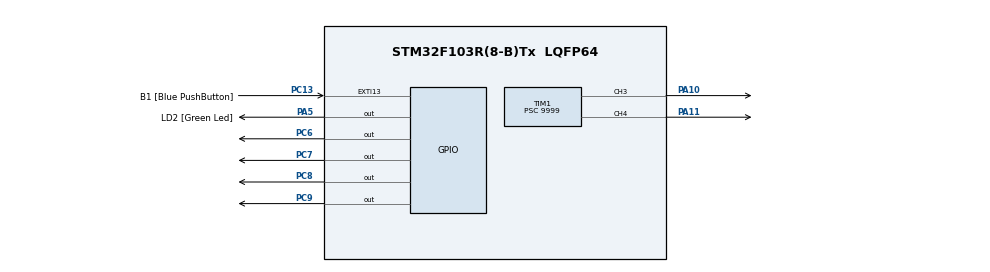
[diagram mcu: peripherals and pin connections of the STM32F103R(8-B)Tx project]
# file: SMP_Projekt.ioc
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Mcu.Family=STM32F1
Mcu.Name=STM32F103R(8-B)Tx
Mcu.Package=LQFP64
NVIC.EXTI15_10_IRQn=true\:0\:0\:false\:false\:true\:true\:true
NVIC.PriorityGroup=NVIC_PRIORITYGROUP_4
PA10.Signal=S_TIM1_CH3
PA11.Signal=S_TIM1_CH4
PA13.GPIO_Label=TMS
PA13.Mode=Serial_Wire
PA13.Signal=SYS_JTMS-SWDIO
PA14.GPIO_Label=TCK
PA14.Mode=Serial_Wire
PA14.Signal=SYS_JTCK-SWCLK
PA2.GPIO_Label=USART_TX
PA2.GPIO_Mode=GPIO_MODE_AF_PP
PA2.GPIO_PuPd=GPIO_NOPULL
PA2.GPIO_Speed=GPIO_SPEED_FREQ_LOW
PA2.Signal=USART2_TX
PA3.GPIO_Label=USART_RX
PA3.GPIO_Mode=GPIO_MODE_AF_PP
PA3.GPIO_PuPd=GPIO_NOPULL
PA3.GPIO_Speed=GPIO_SPEED_FREQ_LOW
PA3.Signal=USART2_RX
PA5.GPIO_Label=LD2 [Green Led]
PA5.GPIO_ModeDefaultOutputPP=GPIO_MODE_OUTPUT_PP
PA5.GPIO_PuPd=GPIO_NOPULL
PA5.GPIO_Speed=GPIO_SPEED_FREQ_LOW
PA5.Signal=GPIO_Output
PB3.GPIO_Label=SWO
PB3.Signal=SYS_JTDO-TRACESWO
PC13-TAMPER-RTC.GPIO_Label=B1 [Blue PushButton]
PC13-TAMPER-RTC.GPIO_ModeDefaultEXTI=GPIO_MODE_IT_FALLING
PC13-TAMPER-RTC.GPIO_PuPd=GPIO_NOPULL
PC13-TAMPER-RTC.Signal=GPXTI13
PC14-OSC32_IN.Signal=RCC_OSC32_IN
PC15-OSC32_OUT.Signal=RCC_OSC32_OUT
PC6.Signal=GPIO_Output
PC7.Signal=GPIO_Output
PC8.Signal=GPIO_Output
PC9.Signal=GPIO_Output
PD0-OSC_IN.Signal=RCC_OSC_IN
PD1-OSC_OUT.Signal=RCC_OSC_OUT
ProjectManager.HeapSize=0x200
ProjectManager.StackSize=0x400
ProjectManager.TargetToolchain=STM32CubeIDE
RCC.AHBFreq_Value=64000000
RCC.APB1CLKDivider=RCC_HCLK_DIV2
RCC.APB1Freq_Value=32000000
RCC.APB1TimFreq_Value=64000000
RCC.APB2CLKDivider=RCC_HCLK_DIV16
RCC.APB2Freq_Value=4000000
RCC.APB2TimCLKDivider=2
RCC.APB2TimFreq_Value=8000000
RCC.HCLKFreq_Value=64000000
RCC.SYSCLKFreq_VALUE=64000000
RCC.SYSCLKSource=RCC_SYSCLKSOURCE_PLLCLK
RCC.USBFreq_Value=64000000
SH.S_TIM1_CH3.0=TIM1_CH3,PWM Generation3 CH3
SH.S_TIM1_CH4.0=TIM1_CH4,PWM Generation4 CH4
TIM1.Channel-PWM\ Generation3\ CH3=TIM_CHANNEL_3
TIM1.Channel-PWM\ Generation4\ CH4=TIM_CHANNEL_4
TIM1.Period=7
TIM1.Prescaler=9999
VP_TIM1_VS_ClockSourceINT.Mode=Internal
board=NUCLEO-F103RB

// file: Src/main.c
/* USER CODE BEGIN Header */
/**
  ******************************************************************************
  * @file           : main.c
  * @brief          : Main program body
  ******************************************************************************
  * @attention
  *
  * <h2><center>&copy; Copyright (c) 2020 STMicroelectronics.
  * All rights reserved.</center></h2>
  *
  * This software component is licensed by ST under BSD 3-Clause license,
  * the "License"; You may not use this file except in compliance with the
  * License. You may obtain a copy of the License at:
  *                        opensource.org/licenses/BSD-3-Clause
  *
  ******************************************************************************
  */
/* USER CODE END Header */

#include "main.h"
#include "tim.h"
#include "gpio.h"

void SystemClock_Config(void);

int main(void)
{

  /* MCU Configuration--------------------------------------------------------*/

  /* Reset of all peripherals, Initializes the Flash interface and the Systick. */
  HAL_Init();

  /* Configure the system clock */
  SystemClock_Config();

  /* Initialize all configured peripherals */
  MX_GPIO_Init();
  MX_TIM1_Init();
  /* USER CODE BEGIN 2 */

  HAL_TIM_PWM_Start(&htim1, TIM_CHANNEL_3);
  HAL_TIM_PWM_Start(&htim1, TIM_CHANNEL_4);

  HAL_GPIO_WritePin(GPIOC, GPIO_PIN_6, GPIO_PIN_SET);
  HAL_GPIO_WritePin(GPIOC, GPIO_PIN_7, GPIO_PIN_RESET);
  HAL_GPIO_WritePin(GPIOC, GPIO_PIN_8, GPIO_PIN_SET);
  HAL_GPIO_WritePin(GPIOC, GPIO_PIN_9, GPIO_PIN_RESET);
  /* USER CODE END 2 */
  /* Infinite loop */
  /* USER CODE BEGIN WHILE */
  TIM1->CCR3 = 8;
  TIM1->CCR4 = 8;

  while (1)
  {
    /* USER CODE END WHILE */
  }
}

void SystemClock_Config(void)
{
  RCC_OscInitTypeDef RCC_OscInitStruct = {0};
  RCC_ClkInitTypeDef RCC_ClkInitStruct = {0};

  /** Initializes the CPU, AHB and APB busses clocks
  */
  RCC_OscInitStruct.OscillatorType = RCC_OSCILLATORTYPE_HSI;
  RCC_OscInitStruct.HSIState = RCC_HSI_ON;
  RCC_OscInitStruct.HSICalibrationValue = RCC_HSICALIBRATION_DEFAULT;
  RCC_OscInitStruct.PLL.PLLState = RCC_PLL_ON;
  RCC_OscInitStruct.PLL.PLLSource = RCC_PLLSOURCE_HSI_DIV2;
  RCC_OscInitStruct.PLL.PLLMUL = RCC_PLL_MUL2;
  if (HAL_RCC_OscConfig(&RCC_OscInitStruct) != HAL_OK)
  {
    Error_Handler();
  }
  /** Initializes the CPU, AHB and APB busses clocks
  */
  RCC_ClkInitStruct.ClockType = RCC_CLOCKTYPE_HCLK|RCC_CLOCKTYPE_SYSCLK
                              |RCC_CLOCKTYPE_PCLK1|RCC_CLOCKTYPE_PCLK2;
  RCC_ClkInitStruct.SYSCLKSource = RCC_SYSCLKSOURCE_PLLCLK;
  RCC_ClkInitStruct.AHBCLKDivider = RCC_SYSCLK_DIV1;
  RCC_ClkInitStruct.APB1CLKDivider = RCC_HCLK_DIV2;
  RCC_ClkInitStruct.APB2CLKDivider = RCC_HCLK_DIV16;

  if (HAL_RCC_ClockConfig(&RCC_ClkInitStruct, FLASH_LATENCY_2) != HAL_OK)
  {
    Error_Handler();
  }
}

void Error_Handler(void)
{
}

/************************ (C) COPYRIGHT STMicroelectronics *****END OF FILE****/
